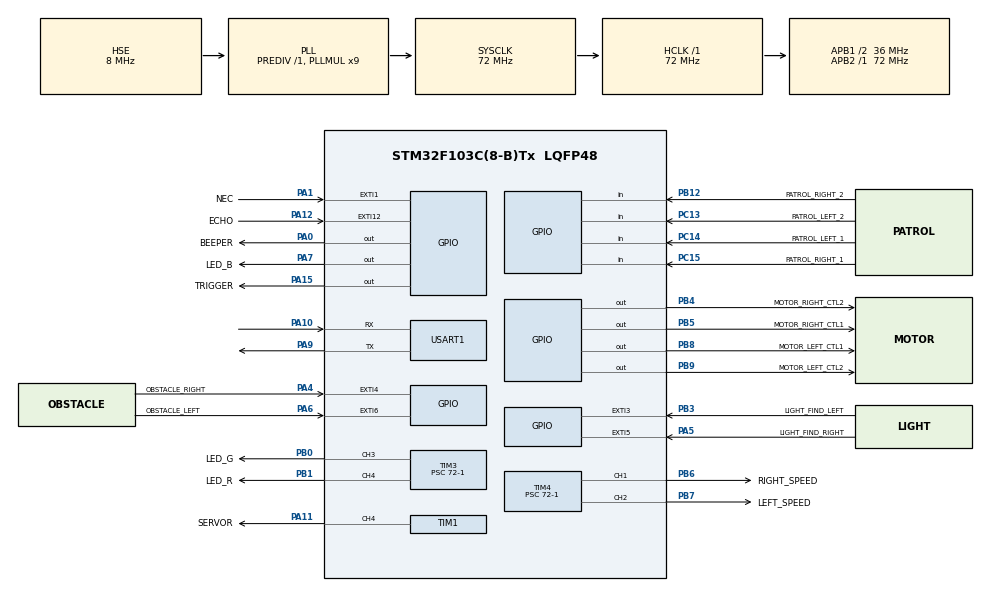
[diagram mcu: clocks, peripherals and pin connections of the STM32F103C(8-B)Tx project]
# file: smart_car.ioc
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Mcu.Family=STM32F1
Mcu.Name=STM32F103C(8-B)Tx
Mcu.Package=LQFP48
NVIC.EXTI15_10_IRQn=true\:0\:0\:false\:false\:true\:true\:true\:true
NVIC.EXTI1_IRQn=true\:0\:0\:false\:false\:true\:true\:true\:true
NVIC.EXTI3_IRQn=true\:1\:0\:true\:false\:true\:true\:true\:true
NVIC.EXTI4_IRQn=true\:1\:0\:true\:false\:true\:true\:true\:true
NVIC.EXTI9_5_IRQn=true\:1\:0\:true\:false\:true\:true\:true\:true
NVIC.PriorityGroup=NVIC_PRIORITYGROUP_4
NVIC.TIM2_IRQn=true\:15\:0\:true\:false\:true\:true\:true\:true
NVIC.TIM3_IRQn=true\:0\:0\:false\:false\:true\:true\:true\:true
PA0-WKUP.GPIO_Label=BEEPER
PA0-WKUP.Signal=GPIO_Output
PA1.GPIO_Label=NEC
PA1.Signal=GPXTI1
PA10.Mode=Asynchronous
PA10.Signal=USART1_RX
PA11.GPIO_Label=SERVOR
PA11.Signal=S_TIM1_CH4
PA12.GPIO_Label=ECHO
PA12.GPIO_ModeDefaultEXTI=GPIO_MODE_IT_RISING_FALLING
PA12.GPIO_PuPd=GPIO_PULLDOWN
PA12.Signal=GPXTI12
PA13.Mode=Serial_Wire
PA13.Signal=SYS_JTMS-SWDIO
PA14.Mode=Serial_Wire
PA14.Signal=SYS_JTCK-SWCLK
PA15.GPIO_Label=TRIGGER
PA15.Signal=GPIO_Output
PA4.GPIO_Label=OBSTACLE_RIGHT
PA4.GPIO_ModeDefaultEXTI=GPIO_MODE_IT_RISING_FALLING
PA4.Signal=GPXTI4
PA5.GPIO_Label=LIGHT_FIND_RIGHT
PA5.GPIO_ModeDefaultEXTI=GPIO_MODE_IT_RISING_FALLING
PA5.Signal=GPXTI5
PA6.GPIO_Label=OBSTACLE_LEFT
PA6.Signal=GPXTI6
PA7.GPIO_Label=LED_B
PA7.Signal=GPIO_Output
PA9.Mode=Asynchronous
PA9.Signal=USART1_TX
PB0.GPIO_Label=LED_G
PB0.Signal=S_TIM3_CH3
PB1.GPIO_Label=LED_R
PB1.Signal=S_TIM3_CH4
PB12.GPIO_Label=PATROL_RIGHT_2
PB12.Signal=GPIO_Input
PB3.GPIO_Label=LIGHT_FIND_LEFT
PB3.GPIO_ModeDefaultEXTI=GPIO_MODE_IT_RISING_FALLING
PB3.Signal=GPXTI3
PB4.GPIO_Label=MOTOR_RIGHT_CTL2
PB4.Signal=GPIO_Output
PB5.GPIO_Label=MOTOR_RIGHT_CTL1
PB5.Signal=GPIO_Output
PB6.GPIO_Label=RIGHT_SPEED
PB6.Signal=S_TIM4_CH1
PB7.GPIO_Label=LEFT_SPEED
PB7.Signal=S_TIM4_CH2
PB8.GPIO_Label=MOTOR_LEFT_CTL1
PB8.Signal=GPIO_Output
PB9.GPIO_Label=MOTOR_LEFT_CTL2
PB9.Signal=GPIO_Output
PC13-TAMPER-RTC.GPIO_Label=PATROL_LEFT_2
PC13-TAMPER-RTC.Signal=GPIO_Input
PC14-OSC32_IN.GPIO_Label=PATROL_LEFT_1
PC14-OSC32_IN.Signal=GPIO_Input
PC15-OSC32_OUT.GPIO_Label=PATROL_RIGHT_1
PC15-OSC32_OUT.Signal=GPIO_Input
PD0-OSC_IN.Mode=HSE-External-Oscillator
PD0-OSC_IN.Signal=RCC_OSC_IN
PD1-OSC_OUT.Mode=HSE-External-Oscillator
PD1-OSC_OUT.Signal=RCC_OSC_OUT
ProjectManager.HeapSize=0x200
ProjectManager.StackSize=0x400
ProjectManager.TargetToolchain=STM32CubeIDE
RCC.AHBFreq_Value=72000000
RCC.APB1CLKDivider=RCC_HCLK_DIV2
RCC.APB1Freq_Value=36000000
RCC.APB1TimFreq_Value=72000000
RCC.APB2Freq_Value=72000000
RCC.APB2TimFreq_Value=72000000
RCC.HCLKFreq_Value=72000000
RCC.PLLMUL=RCC_PLL_MUL9
RCC.PLLSourceVirtual=RCC_PLLSOURCE_HSE
RCC.SYSCLKFreq_VALUE=72000000
RCC.SYSCLKSource=RCC_SYSCLKSOURCE_PLLCLK
RCC.TimSys_Div=SYSTICK_CLKSOURCE_HCLK_DIV8
RCC.USBFreq_Value=72000000
SH.S_TIM1_CH4.0=TIM1_CH4,PWM Generation4 CH4
SH.S_TIM3_CH3.0=TIM3_CH3,PWM Generation3 CH3
SH.S_TIM3_CH4.0=TIM3_CH4,PWM Generation4 CH4
SH.S_TIM4_CH1.0=TIM4_CH1,PWM Generation1 CH1
SH.S_TIM4_CH2.0=TIM4_CH2,PWM Generation2 CH2
TIM1.Channel-PWM\ Generation4\ CH4=TIM_CHANNEL_4
TIM1.Period=20000-1
TIM1.Prescaler=72-1
TIM2.Period=1000
TIM2.Prescaler=72
TIM3.Channel-PWM\ Generation3\ CH3=TIM_CHANNEL_3
TIM3.Channel-PWM\ Generation4\ CH4=TIM_CHANNEL_4
TIM3.Period=1000-1
TIM3.Prescaler=72-1
TIM4.AutoReloadPreload=TIM_AUTORELOAD_PRELOAD_ENABLE
TIM4.Channel-PWM\ Generation1\ CH1=TIM_CHANNEL_1
TIM4.Channel-PWM\ Generation2\ CH2=TIM_CHANNEL_2
TIM4.Period=1000-1
TIM4.Prescaler=72-1
USART1.VirtualMode=VM_ASYNC
VP_TIM2_VS_ClockSourceINT.Mode=Internal
board=custom

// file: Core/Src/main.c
/* USER CODE BEGIN Header */
/**
  ******************************************************************************
  * @file           : main.c
  * @brief          : Main program body
  ******************************************************************************
  * @attention
  *
  * Copyright (c) 2024 STMicroelectronics.
  * All rights reserved.
  *
  * This software is licensed under terms that can be found in the LICENSE file
  * in the root directory of this software component.
  * If no LICENSE file comes with this software, it is provided AS-IS.
  *
  ******************************************************************************
  */
/* USER CODE END Header */
#include "main.h"

/* USER CODE BEGIN Includes */
#include <stdio.h>

#include "delay.h"
#include "fan.h"
#include "rgb_led.h"
#include "patrol_line.h"
#include "servor.h"
#include "motor.h"
#include "schedule.h"
#include "hc_sr04.h"
/* USER CODE END Includes */

TIM_HandleTypeDef htim1;
TIM_HandleTypeDef htim2;
TIM_HandleTypeDef htim3;
TIM_HandleTypeDef htim4;

UART_HandleTypeDef huart1;

void SystemClock_Config(void);

static void MX_GPIO_Init(void);

static void MX_USART1_UART_Init(void);

static void MX_TIM4_Init(void);

static void MX_TIM1_Init(void);

static void MX_TIM3_Init(void);

static void MX_TIM2_Init(void);

int main(void) {

    /* MCU Configuration--------------------------------------------------------*/

    /* Reset of all peripherals, Initializes the Flash interface and the Systick. */
    HAL_Init();

    /* Configure the system clock */
    SystemClock_Config();

    /* USER CODE BEGIN SysInit */
    delay_init(72);
    /* USER CODE END SysInit */

    /* Initialize all configured peripherals */
    MX_GPIO_Init();
    MX_USART1_UART_Init();
    MX_TIM4_Init();
    MX_TIM1_Init();
    MX_TIM3_Init();
    MX_TIM2_Init();
    /* USER CODE BEGIN 2 */
    fan_off();
    LED_Config_t config = {
        .R_value = 200,
        .G_value = 2,
        .B_value = 5
    };
    led_config(config);
    // LeftMotor_Control(50);
    // RightMotor_Control(150);
    // servor_set_angle(0);
    /* USER CODE END 2 */

    /* Infinite loop */
    /* USER CODE BEGIN WHILE */
    schedule_start();
    hc_sr04_start(500);
    while (1) {
        // while (config.R_value) {
        // config.R_value++;
        // led_config(config);
        // HAL_Delay(5);
        // }
        // while (config.G_value) {
        // config.G_value++;
        // led_config(config);
        // HAL_Delay(5);
        // }
        // while (config.B_value) {
        // config.B_value++;
        // led_config(config);
        // HAL_Delay(5);
        // }
        // config.R_value = 1;
        // config.G_value = 1;
        // config.B_value = 1;

        HAL_Delay(500);
        // uint8_t patrol_data = get_patrol_data();
        // printf("%d\r\n", patrol_data);

        /* USER CODE END WHILE */

    }
}

void SystemClock_Config(void) {
    RCC_OscInitTypeDef RCC_OscInitStruct = {0};
    RCC_ClkInitTypeDef RCC_ClkInitStruct = {0};

    /** Initializes the RCC Oscillators according to the specified parameters
    * in the RCC_OscInitTypeDef structure.
    */
    RCC_OscInitStruct.OscillatorType = RCC_OSCILLATORTYPE_HSE;
    RCC_OscInitStruct.HSEState = RCC_HSE_ON;
    RCC_OscInitStruct.HSEPredivValue = RCC_HSE_PREDIV_DIV1;
    RCC_OscInitStruct.HSIState = RCC_HSI_ON;
    RCC_OscInitStruct.PLL.PLLState = RCC_PLL_ON;
    RCC_OscInitStruct.PLL.PLLSource = RCC_PLLSOURCE_HSE;
    RCC_OscInitStruct.PLL.PLLMUL = RCC_PLL_MUL9;
    if (HAL_RCC_OscConfig(&RCC_OscInitStruct) != HAL_OK) {
        Error_Handler();
    }

    /** Initializes the CPU, AHB and APB buses clocks
    */
    RCC_ClkInitStruct.ClockType = RCC_CLOCKTYPE_HCLK | RCC_CLOCKTYPE_SYSCLK
                                  | RCC_CLOCKTYPE_PCLK1 | RCC_CLOCKTYPE_PCLK2;
    RCC_ClkInitStruct.SYSCLKSource = RCC_SYSCLKSOURCE_PLLCLK;
    RCC_ClkInitStruct.AHBCLKDivider = RCC_SYSCLK_DIV1;
    RCC_ClkInitStruct.APB1CLKDivider = RCC_HCLK_DIV2;
    RCC_ClkInitStruct.APB2CLKDivider = RCC_HCLK_DIV1;

    if (HAL_RCC_ClockConfig(&RCC_ClkInitStruct, FLASH_LATENCY_2) != HAL_OK) {
        Error_Handler();
    }
}

static void MX_TIM1_Init(void) {

    TIM_MasterConfigTypeDef sMasterConfig = {0};
    TIM_OC_InitTypeDef sConfigOC = {0};
    TIM_BreakDeadTimeConfigTypeDef sBreakDeadTimeConfig = {0};

    htim1.Instance = TIM1;
    htim1.Init.Prescaler = 72 - 1;
    htim1.Init.CounterMode = TIM_COUNTERMODE_UP;
    htim1.Init.Period = 20000 - 1;
    htim1.Init.ClockDivision = TIM_CLOCKDIVISION_DIV1;
    htim1.Init.RepetitionCounter = 0;
    htim1.Init.AutoReloadPreload = TIM_AUTORELOAD_PRELOAD_DISABLE;
    if (HAL_TIM_PWM_Init(&htim1) != HAL_OK) {
        Error_Handler();
    }
    sMasterConfig.MasterOutputTrigger = TIM_TRGO_RESET;
    sMasterConfig.MasterSlaveMode = TIM_MASTERSLAVEMODE_DISABLE;
    if (HAL_TIMEx_MasterConfigSynchronization(&htim1, &sMasterConfig) != HAL_OK) {
        Error_Handler();
    }
    sConfigOC.OCMode = TIM_OCMODE_PWM1;
    sConfigOC.Pulse = 0;
    sConfigOC.OCPolarity = TIM_OCPOLARITY_HIGH;
    sConfigOC.OCFastMode = TIM_OCFAST_DISABLE;
    sConfigOC.OCIdleState = TIM_OCIDLESTATE_RESET;
    sConfigOC.OCNIdleState = TIM_OCNIDLESTATE_RESET;
    if (HAL_TIM_PWM_ConfigChannel(&htim1, &sConfigOC, TIM_CHANNEL_4) != HAL_OK) {
        Error_Handler();
    }
    sBreakDeadTimeConfig.OffStateRunMode = TIM_OSSR_DISABLE;
    sBreakDeadTimeConfig.OffStateIDLEMode = TIM_OSSI_DISABLE;
    sBreakDeadTimeConfig.LockLevel = TIM_LOCKLEVEL_OFF;
    sBreakDeadTimeConfig.DeadTime = 0;
    sBreakDeadTimeConfig.BreakState = TIM_BREAK_DISABLE;
    sBreakDeadTimeConfig.BreakPolarity = TIM_BREAKPOLARITY_HIGH;
    sBreakDeadTimeConfig.AutomaticOutput = TIM_AUTOMATICOUTPUT_DISABLE;
    if (HAL_TIMEx_ConfigBreakDeadTime(&htim1, &sBreakDeadTimeConfig) != HAL_OK) {
        Error_Handler();
    }
    HAL_TIM_MspPostInit(&htim1);
}

static void MX_TIM2_Init(void) {

    TIM_ClockConfigTypeDef sClockSourceConfig = {0};
    TIM_MasterConfigTypeDef sMasterConfig = {0};

    htim2.Instance = TIM2;
    htim2.Init.Prescaler = 72;
    htim2.Init.CounterMode = TIM_COUNTERMODE_UP;
    htim2.Init.Period = 1000;
    htim2.Init.ClockDivision = TIM_CLOCKDIVISION_DIV1;
    htim2.Init.AutoReloadPreload = TIM_AUTORELOAD_PRELOAD_DISABLE;
    if (HAL_TIM_Base_Init(&htim2) != HAL_OK) {
        Error_Handler();
    }
    sClockSourceConfig.ClockSource = TIM_CLOCKSOURCE_INTERNAL;
    if (HAL_TIM_ConfigClockSource(&htim2, &sClockSourceConfig) != HAL_OK) {
        Error_Handler();
    }
    sMasterConfig.MasterOutputTrigger = TIM_TRGO_RESET;
    sMasterConfig.MasterSlaveMode = TIM_MASTERSLAVEMODE_DISABLE;
    if (HAL_TIMEx_MasterConfigSynchronization(&htim2, &sMasterConfig) != HAL_OK) {
        Error_Handler();
    }
}

static void MX_TIM3_Init(void) {

    TIM_MasterConfigTypeDef sMasterConfig = {0};
    TIM_OC_InitTypeDef sConfigOC = {0};

    htim3.Instance = TIM3;
    htim3.Init.Prescaler = 72 - 1;
    htim3.Init.CounterMode = TIM_COUNTERMODE_UP;
    htim3.Init.Period = 1000 - 1;
    htim3.Init.ClockDivision = TIM_CLOCKDIVISION_DIV1;
    htim3.Init.AutoReloadPreload = TIM_AUTORELOAD_PRELOAD_DISABLE;
    if (HAL_TIM_PWM_Init(&htim3) != HAL_OK) {
        Error_Handler();
    }
    sMasterConfig.MasterOutputTrigger = TIM_TRGO_RESET;
    sMasterConfig.MasterSlaveMode = TIM_MASTERSLAVEMODE_DISABLE;
    if (HAL_TIMEx_MasterConfigSynchronization(&htim3, &sMasterConfig) != HAL_OK) {
        Error_Handler();
    }
    sConfigOC.OCMode = TIM_OCMODE_PWM1;
    sConfigOC.Pulse = 0;
    sConfigOC.OCPolarity = TIM_OCPOLARITY_HIGH;
    sConfigOC.OCFastMode = TIM_OCFAST_DISABLE;
    if (HAL_TIM_PWM_ConfigChannel(&htim3, &sConfigOC, TIM_CHANNEL_2) != HAL_OK) {
        Error_Handler();
    }
    if (HAL_TIM_PWM_ConfigChannel(&htim3, &sConfigOC, TIM_CHANNEL_3) != HAL_OK) {
        Error_Handler();
    }
    if (HAL_TIM_PWM_ConfigChannel(&htim3, &sConfigOC, TIM_CHANNEL_4) != HAL_OK) {
        Error_Handler();
    }
    HAL_TIM_MspPostInit(&htim3);
}

static void MX_TIM4_Init(void) {

    TIM_MasterConfigTypeDef sMasterConfig = {0};
    TIM_OC_InitTypeDef sConfigOC = {0};

    htim4.Instance = TIM4;
    htim4.Init.Prescaler = 72 - 1;
    htim4.Init.CounterMode = TIM_COUNTERMODE_UP;
    htim4.Init.Period = 1000 - 1;
    htim4.Init.ClockDivision = TIM_CLOCKDIVISION_DIV1;
    htim4.Init.AutoReloadPreload = TIM_AUTORELOAD_PRELOAD_ENABLE;
    if (HAL_TIM_PWM_Init(&htim4) != HAL_OK) {
        Error_Handler();
    }
    sMasterConfig.MasterOutputTrigger = TIM_TRGO_RESET;
    sMasterConfig.MasterSlaveMode = TIM_MASTERSLAVEMODE_DISABLE;
    if (HAL_TIMEx_MasterConfigSynchronization(&htim4, &sMasterConfig) != HAL_OK) {
        Error_Handler();
    }
    sConfigOC.OCMode = TIM_OCMODE_PWM1;
    sConfigOC.Pulse = 0;
    sConfigOC.OCPolarity = TIM_OCPOLARITY_HIGH;
    sConfigOC.OCFastMode = TIM_OCFAST_DISABLE;
    if (HAL_TIM_PWM_ConfigChannel(&htim4, &sConfigOC, TIM_CHANNEL_1) != HAL_OK) {
        Error_Handler();
    }
    if (HAL_TIM_PWM_ConfigChannel(&htim4, &sConfigOC, TIM_CHANNEL_2) != HAL_OK) {
        Error_Handler();
    }
    HAL_TIM_MspPostInit(&htim4);
}

static void MX_USART1_UART_Init(void) {

    huart1.Instance = USART1;
    huart1.Init.BaudRate = 115200;
    huart1.Init.WordLength = UART_WORDLENGTH_8B;
    huart1.Init.StopBits = UART_STOPBITS_1;
    huart1.Init.Parity = UART_PARITY_NONE;
    huart1.Init.Mode = UART_MODE_TX_RX;
    huart1.Init.HwFlowCtl = UART_HWCONTROL_NONE;
    huart1.Init.OverSampling = UART_OVERSAMPLING_16;
    if (HAL_UART_Init(&huart1) != HAL_OK) {
        Error_Handler();
    }
}

static void MX_GPIO_Init(void) {
    GPIO_InitTypeDef GPIO_InitStruct = {0};

    /* GPIO Ports Clock Enable */
    __HAL_RCC_GPIOC_CLK_ENABLE();
    __HAL_RCC_GPIOD_CLK_ENABLE();
    __HAL_RCC_GPIOA_CLK_ENABLE();
    __HAL_RCC_GPIOB_CLK_ENABLE();

    /*Configure GPIO pin Output Level */
    HAL_GPIO_WritePin(GPIOA, FAN_Pin | TRIGGER_Pin, GPIO_PIN_RESET);

    /*Configure GPIO pin Output Level */
    HAL_GPIO_WritePin(GPIOB, MOTOR_RIGHT_CTL2_Pin | MOTOR_RIGHT_CTL1_Pin | MOTOR_LEFT_CTL1_Pin | MOTOR_LEFT_CTL2_Pin,
                      GPIO_PIN_RESET);

    /*Configure GPIO pins : PATROL_LEFT_2_Pin PATROL_LEFT_1_Pin PATROL_RIGHT_1_Pin */
    GPIO_InitStruct.Pin = PATROL_LEFT_2_Pin | PATROL_LEFT_1_Pin | PATROL_RIGHT_1_Pin;
    GPIO_InitStruct.Mode = GPIO_MODE_INPUT;
    GPIO_InitStruct.Pull = GPIO_NOPULL;
    HAL_GPIO_Init(GPIOC, &GPIO_InitStruct);

    /*Configure GPIO pin : KEY_Pin */
    GPIO_InitStruct.Pin = KEY_Pin;
    GPIO_InitStruct.Mode = GPIO_MODE_IT_RISING;
    GPIO_InitStruct.Pull = GPIO_NOPULL;
    HAL_GPIO_Init(KEY_GPIO_Port, &GPIO_InitStruct);

    /*Configure GPIO pin : FAN_Pin */
    GPIO_InitStruct.Pin = FAN_Pin;
    GPIO_InitStruct.Mode = GPIO_MODE_OUTPUT_PP;
    GPIO_InitStruct.Pull = GPIO_PULLUP;
    GPIO_InitStruct.Speed = GPIO_SPEED_FREQ_LOW;
    HAL_GPIO_Init(FAN_GPIO_Port, &GPIO_InitStruct);

    /*Configure GPIO pins : LIGHT_FIND_LEFT_Pin INFRARED_RIGHT_Pin LIGHT_FIND_RIGHT_Pin INFRARED_LEFT_Pin */
    GPIO_InitStruct.Pin = LIGHT_FIND_LEFT_Pin | INFRARED_RIGHT_Pin | LIGHT_FIND_RIGHT_Pin | INFRARED_LEFT_Pin;
    GPIO_InitStruct.Mode = GPIO_MODE_INPUT;
    GPIO_InitStruct.Pull = GPIO_NOPULL;
    HAL_GPIO_Init(GPIOA, &GPIO_InitStruct);

    /*Configure GPIO pin : PATROL_RIGHT_2_Pin */
    GPIO_InitStruct.Pin = PATROL_RIGHT_2_Pin;
    GPIO_InitStruct.Mode = GPIO_MODE_INPUT;
    GPIO_InitStruct.Pull = GPIO_NOPULL;
    HAL_GPIO_Init(PATROL_RIGHT_2_GPIO_Port, &GPIO_InitStruct);

    /*Configure GPIO pin : ECHO_Pin */
    GPIO_InitStruct.Pin = ECHO_Pin;
    GPIO_InitStruct.Mode = GPIO_MODE_IT_RISING_FALLING;
    GPIO_InitStruct.Pull = GPIO_PULLDOWN;
    HAL_GPIO_Init(ECHO_GPIO_Port, &GPIO_InitStruct);

    /*Configure GPIO pin : TRIGGER_Pin */
    GPIO_InitStruct.Pin = TRIGGER_Pin;
    GPIO_InitStruct.Mode = GPIO_MODE_OUTPUT_PP;
    GPIO_InitStruct.Pull = GPIO_NOPULL;
    GPIO_InitStruct.Speed = GPIO_SPEED_FREQ_LOW;
    HAL_GPIO_Init(TRIGGER_GPIO_Port, &GPIO_InitStruct);

    /*Configure GPIO pins : MOTOR_RIGHT_CTL2_Pin MOTOR_RIGHT_CTL1_Pin MOTOR_LEFT_CTL1_Pin MOTOR_LEFT_CTL2_Pin */
    GPIO_InitStruct.Pin = MOTOR_RIGHT_CTL2_Pin | MOTOR_RIGHT_CTL1_Pin | MOTOR_LEFT_CTL1_Pin | MOTOR_LEFT_CTL2_Pin;
    GPIO_InitStruct.Mode = GPIO_MODE_OUTPUT_PP;
    GPIO_InitStruct.Pull = GPIO_NOPULL;
    GPIO_InitStruct.Speed = GPIO_SPEED_FREQ_LOW;
    HAL_GPIO_Init(GPIOB, &GPIO_InitStruct);

    /* EXTI interrupt init*/
    HAL_NVIC_SetPriority(EXTI15_10_IRQn, 0, 0);
    HAL_NVIC_EnableIRQ(EXTI15_10_IRQn);

}

void Error_Handler(void) {
    __disable_irq();
    while (1) {
    }
}
